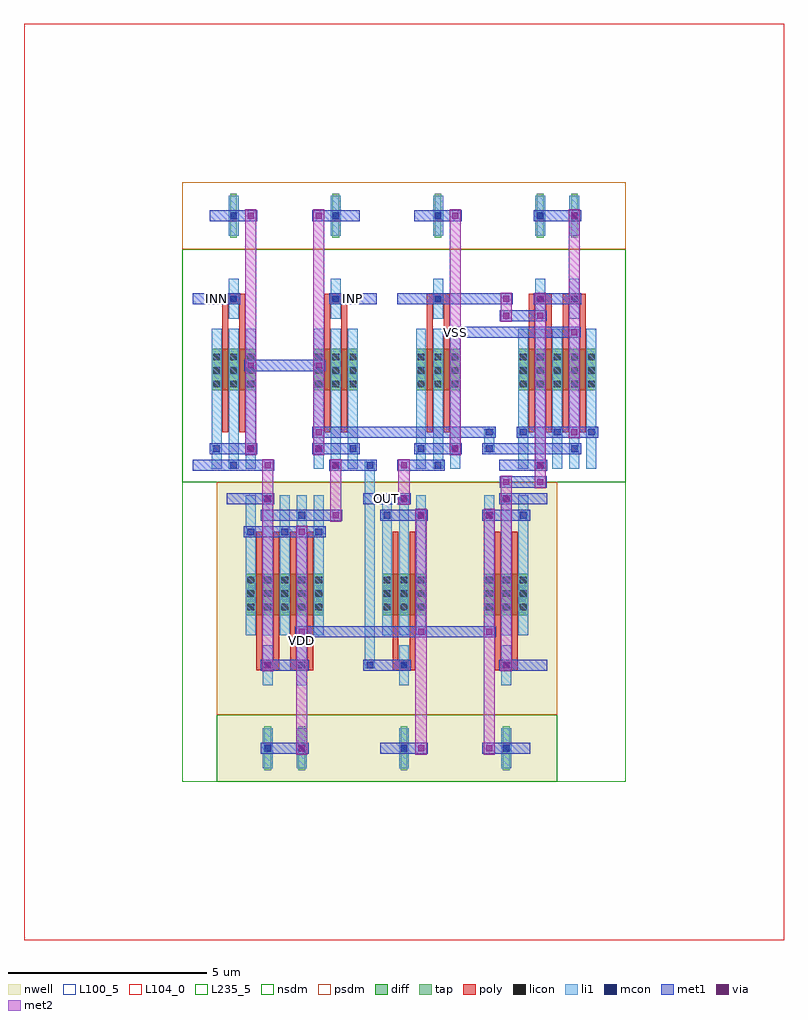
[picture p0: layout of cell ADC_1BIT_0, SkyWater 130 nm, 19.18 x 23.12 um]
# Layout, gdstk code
from math import pi, radians
import gdstk
lib = gdstk.Library(unit=1e-6, precision=1e-09)
def R(c, l, rs):  # rectangles x0, y0, x1, y1
    for r in rs: c.add(gdstk.rectangle(r[:2], r[2:], *l))
def A(c, l, x, y, w, h, nx, ny, dx, dy):  # array of equal rectangles
    R(c, l, [(x+i*dx, y+j*dy, x+i*dx+w, y+j*dy+h) for i in range(nx) for j in range(ny)])
def P(c, l, *ps):  # polygons
    for p in ps: c.add(gdstk.Polygon(p, *l))
nwell = (64, 20)
diff = (65, 20)
tap = (65, 44)
poly = (66, 20)
licon = (66, 44)
li1 = (67, 20)
mcon = (67, 44)
met1 = (68, 20)
via = (68, 44)
met2 = (69, 20)
nsdm = (93, 44)
psdm = (94, 20)
L100_5 = (100, 5)
L104_0 = (104, 0)
L235_5 = (235, 5)

scm_nmos_43308780_x1_y1_ = lib.new_cell('SCM_NMOS_43308780_X1_Y1_1727355101_1727355100')
R(scm_nmos_43308780_x1_y1_, diff, [(0.735,2.31,2.705,3.36)])
R(scm_nmos_43308780_x1_y1_, tap, [(1.205,6.16,1.375,7.28), (2.065,6.16,2.235,7.28)])
A(scm_nmos_43308780_x1_y1_, poly, 1, 1.26, 0.15, 3.36, 4, 1, 0.43, 0)
R(scm_nmos_43308780_x1_y1_, poly, [(1,4.485,1.58,4.755), (1.86,4.485,2.44,4.755)])
A(scm_nmos_43308780_x1_y1_, licon, 0.775, 2.39, 0.17, 0.17, 3, 3, 0.43, 0.34)
A(scm_nmos_43308780_x1_y1_, licon, 1.635, 2.39, 0.17, 0.17, 3, 3, 0.43, 0.34)
R(scm_nmos_43308780_x1_y1_, licon, [(1.205,4.535,1.375,4.705), (2.065,4.535,2.235,4.705), (1.205,6.635,1.375,6.805), (2.065,6.635,2.235,6.805)])
A(scm_nmos_43308780_x1_y1_, li1, 0.735, 0.335, 0.25, 3.53, 5, 1, 0.43, 0)
R(scm_nmos_43308780_x1_y1_, li1, [(1.165,4.115,1.415,5.125), (2.025,4.115,2.275,5.125), (1.165,6.215,1.415,7.225), (2.025,6.215,2.275,7.225)])
A(scm_nmos_43308780_x1_y1_, mcon, 0.775, 1.175, 0.17, 0.17, 3, 1, 0.86, 0)
R(scm_nmos_43308780_x1_y1_, mcon, [(1.205,0.335,1.375,0.505), (2.065,0.755,2.235,0.925), (1.205,4.535,1.375,4.705), (2.065,4.535,2.235,4.705), (1.205,6.635,1.375,6.805), (2.065,6.635,2.235,6.805)])
R(scm_nmos_43308780_x1_y1_, met1, [(0.26,0.28,1.46,0.56), (1.12,0.7,2.32,0.98), (0.69,1.12,2.75,1.4), (1.12,4.48,2.32,4.76), (1.12,6.58,2.32,6.86)])
R(scm_nmos_43308780_x1_y1_, via, [(1.215,0.345,1.365,0.495), (2.075,1.185,2.225,1.335), (1.215,4.545,1.365,4.695), (2.075,6.645,2.225,6.795)])
R(scm_nmos_43308780_x1_y1_, met2, [(1.15,0.26,1.43,4.78), (2.01,1.1,2.29,6.88)])
R(scm_nmos_43308780_x1_y1_, nsdm, [(0,0,3.44,5.88)])
R(scm_nmos_43308780_x1_y1_, psdm, [(0,5.88,3.44,7.56)])
R(scm_nmos_43308780_x1_y1_, L100_5, [(0,0,3.44,7.56)])

nmos_s_54487678_x1_y1_17 = lib.new_cell('NMOS_S_54487678_X1_Y1_1727355100_1727355100')
R(nmos_s_54487678_x1_y1_17, diff, [(0.735,2.31,1.845,3.36)])
R(nmos_s_54487678_x1_y1_17, tap, [(1.205,6.16,1.375,7.28)])
R(nmos_s_54487678_x1_y1_17, poly, [(1,1.26,1.15,4.62), (1.43,1.26,1.58,4.62), (1,4.485,1.58,4.755)])
A(nmos_s_54487678_x1_y1_17, licon, 0.775, 2.39, 0.17, 0.17, 3, 3, 0.43, 0.34)
R(nmos_s_54487678_x1_y1_17, licon, [(1.205,4.535,1.375,4.705), (1.205,6.635,1.375,6.805)])
A(nmos_s_54487678_x1_y1_17, li1, 0.735, 0.335, 0.25, 3.53, 3, 1, 0.43, 0)
R(nmos_s_54487678_x1_y1_17, li1, [(1.165,4.115,1.415,5.125), (1.165,6.215,1.415,7.225)])
R(nmos_s_54487678_x1_y1_17, mcon, [(1.205,0.335,1.375,0.505), (0.775,0.755,0.945,0.925), (1.635,0.755,1.805,0.925), (1.205,4.535,1.375,4.705), (1.205,6.635,1.375,6.805)])
R(nmos_s_54487678_x1_y1_17, met1, [(0.26,0.28,1.46,0.56), (0.69,0.7,1.89,0.98), (0.26,4.48,1.46,4.76), (0.69,6.58,1.89,6.86)])
R(nmos_s_54487678_x1_y1_17, via, [(1.645,0.765,1.795,0.915), (1.645,6.645,1.795,6.795)])
R(nmos_s_54487678_x1_y1_17, met2, [(1.58,0.68,1.86,6.88)])
R(nmos_s_54487678_x1_y1_17, nsdm, [(0,0,2.58,5.88)])
R(nmos_s_54487678_x1_y1_17, psdm, [(0,5.88,2.58,7.56)])
R(nmos_s_54487678_x1_y1_17, L100_5, [(0,0,2.58,7.56)])

cmb_nmos_2_43145097_0_0_ = lib.new_cell('CMB_NMOS_2_43145097_0_0_1727355100')
R(cmb_nmos_2_43145097_0_0_, met1, [(1.56,3.64,1.88,3.92), (1.56,3.64,1.88,3.92), (1.72,3.64,4.73,3.92), (4.57,3.64,4.89,3.92), (4.57,3.64,4.89,3.92), (2.85,4.06,3.17,4.34), (2.85,4.06,3.17,4.34), (3.01,4.06,3.87,4.34), (3.71,4.06,4.03,4.34), (3.71,4.06,4.03,4.34), (1.29,4.48,3.01,4.76), (2.85,4.48,3.17,4.76), (2.85,4.48,3.17,4.76)])
P(cmb_nmos_2_43145097_0_0_, met1, [(0,0),(0,0),(0,0),(0,0)],
  [(0,0),(0,0),(0,0),(0,0)],
  [(0,0),(0,0),(0,0),(0,0)])
R(cmb_nmos_2_43145097_0_0_, via, [(1.645,3.705,1.795,3.855), (1.645,3.705,1.795,3.855), (4.655,3.705,4.805,3.855), (4.655,3.705,4.805,3.855), (2.935,4.125,3.085,4.275), (2.935,4.125,3.085,4.275), (3.795,4.125,3.945,4.275), (3.795,4.125,3.945,4.275), (2.935,4.545,3.085,4.695), (2.935,4.545,3.085,4.695)])
R(cmb_nmos_2_43145097_0_0_, met2, [(1.58,3.62,1.86,3.94), (1.58,3.62,1.86,3.94), (4.59,3.62,4.87,3.94), (4.59,3.62,4.87,3.94), (2.87,4.04,3.15,4.36), (2.87,4.04,3.15,4.36), (3.73,4.04,4.01,4.36), (3.73,4.04,4.01,4.36), (2.87,4.2,3.15,4.62), (2.87,4.46,3.15,4.78), (2.87,4.46,3.15,4.78)])
P(cmb_nmos_2_43145097_0_0_, met2, [(0,0),(0,0),(0,0),(0,0)],
  [(0,0),(0,0),(0,0),(0,0)],
  [(0,0),(0,0),(0,0),(0,0)])
R(cmb_nmos_2_43145097_0_0_, L235_5, [(0,0,6.02,7.56)])
cmb_nmos_2_43145097_0_0_.add(gdstk.Reference(scm_nmos_43308780_x1_y1_, (2.58,0)))
cmb_nmos_2_43145097_0_0_.add(gdstk.Reference(nmos_s_54487678_x1_y1_17, (0,0)))

scm_pmos_7675836_x1_y1_1 = lib.new_cell('SCM_PMOS_7675836_X1_Y1_1727355104')
R(scm_pmos_7675836_x1_y1_1, nwell, [(0,0,3.44,7.56)])
R(scm_pmos_7675836_x1_y1_1, diff, [(0.735,2.31,2.705,3.36)])
R(scm_pmos_7675836_x1_y1_1, tap, [(1.205,6.16,1.375,7.28), (2.065,6.16,2.235,7.28)])
A(scm_pmos_7675836_x1_y1_1, poly, 1, 1.26, 0.15, 3.36, 4, 1, 0.43, 0)
R(scm_pmos_7675836_x1_y1_1, poly, [(1,4.485,1.58,4.755), (1.86,4.485,2.44,4.755)])
A(scm_pmos_7675836_x1_y1_1, licon, 0.775, 2.39, 0.17, 0.17, 3, 3, 0.43, 0.34)
A(scm_pmos_7675836_x1_y1_1, licon, 1.635, 2.39, 0.17, 0.17, 3, 3, 0.43, 0.34)
R(scm_pmos_7675836_x1_y1_1, licon, [(1.205,4.535,1.375,4.705), (2.065,4.535,2.235,4.705), (1.205,6.635,1.375,6.805), (2.065,6.635,2.235,6.805)])
A(scm_pmos_7675836_x1_y1_1, li1, 0.735, 0.335, 0.25, 3.53, 5, 1, 0.43, 0)
R(scm_pmos_7675836_x1_y1_1, li1, [(1.165,4.115,1.415,5.125), (2.025,4.115,2.275,5.125), (1.165,6.215,1.415,7.225), (2.025,6.215,2.275,7.225)])
A(scm_pmos_7675836_x1_y1_1, mcon, 0.775, 1.175, 0.17, 0.17, 3, 1, 0.86, 0)
R(scm_pmos_7675836_x1_y1_1, mcon, [(1.205,0.335,1.375,0.505), (2.065,0.755,2.235,0.925), (1.205,4.535,1.375,4.705), (2.065,4.535,2.235,4.705), (1.205,6.635,1.375,6.805), (2.065,6.635,2.235,6.805)])
R(scm_pmos_7675836_x1_y1_1, met1, [(0.26,0.28,1.46,0.56), (1.12,0.7,2.32,0.98), (0.69,1.12,2.75,1.4), (1.12,4.48,2.32,4.76), (1.12,6.58,2.32,6.86)])
R(scm_pmos_7675836_x1_y1_1, via, [(1.215,0.345,1.365,0.495), (2.075,1.185,2.225,1.335), (1.215,4.545,1.365,4.695), (2.075,6.645,2.225,6.795)])
R(scm_pmos_7675836_x1_y1_1, met2, [(1.15,0.26,1.43,4.78), (2.01,1.1,2.29,6.88)])
R(scm_pmos_7675836_x1_y1_1, nsdm, [(0,5.88,3.44,7.56)])
R(scm_pmos_7675836_x1_y1_1, psdm, [(0,0,3.44,5.88)])
R(scm_pmos_7675836_x1_y1_1, L100_5, [(0,0,3.44,7.56)])

dcl_pmos_s_36446492_x1_y = lib.new_cell('DCL_PMOS_S_36446492_X1_Y1_1727355101')
R(dcl_pmos_s_36446492_x1_y, nwell, [(0,0,2.58,7.56)])
R(dcl_pmos_s_36446492_x1_y, diff, [(0.735,2.31,1.845,3.36)])
R(dcl_pmos_s_36446492_x1_y, tap, [(1.205,6.16,1.375,7.28)])
R(dcl_pmos_s_36446492_x1_y, poly, [(1,1.26,1.15,4.62), (1.43,1.26,1.58,4.62), (1,4.485,1.58,4.755)])
A(dcl_pmos_s_36446492_x1_y, licon, 0.775, 2.39, 0.17, 0.17, 3, 3, 0.43, 0.34)
R(dcl_pmos_s_36446492_x1_y, licon, [(1.205,4.535,1.375,4.705), (1.205,6.635,1.375,6.805)])
A(dcl_pmos_s_36446492_x1_y, li1, 0.735, 0.335, 0.25, 3.53, 3, 1, 0.43, 0)
R(dcl_pmos_s_36446492_x1_y, li1, [(1.165,4.115,1.415,5.125), (1.165,6.215,1.415,7.225)])
R(dcl_pmos_s_36446492_x1_y, mcon, [(1.205,0.335,1.375,0.505), (0.775,0.755,0.945,0.925), (1.635,0.755,1.805,0.925), (1.205,4.535,1.375,4.705), (1.205,6.635,1.375,6.805)])
R(dcl_pmos_s_36446492_x1_y, met1, [(0.26,0.28,1.46,0.56), (0.69,0.7,1.89,0.98), (0.26,4.48,1.46,4.76), (0.69,6.58,1.89,6.86)])
R(dcl_pmos_s_36446492_x1_y, via, [(1.215,0.345,1.365,0.495), (1.645,0.765,1.795,0.915), (1.215,4.545,1.365,4.695), (1.645,6.645,1.795,6.795)])
R(dcl_pmos_s_36446492_x1_y, met2, [(1.15,0.26,1.43,4.78), (1.58,0.68,1.86,6.88)])
R(dcl_pmos_s_36446492_x1_y, nsdm, [(0,5.88,2.58,7.56)])
R(dcl_pmos_s_36446492_x1_y, psdm, [(0,0,2.58,5.88)])
R(dcl_pmos_s_36446492_x1_y, L100_5, [(0,0,2.58,7.56)])

c_nmos_s_54487678_x1_y1_17 = lib.new_cell('NMOS_S_54487678_X1_Y1_1727355102')
R(c_nmos_s_54487678_x1_y1_17, diff, [(0.735,2.31,1.845,3.36)])
R(c_nmos_s_54487678_x1_y1_17, tap, [(1.205,6.16,1.375,7.28)])
R(c_nmos_s_54487678_x1_y1_17, poly, [(1,1.26,1.15,4.62), (1.43,1.26,1.58,4.62), (1,4.485,1.58,4.755)])
A(c_nmos_s_54487678_x1_y1_17, licon, 0.775, 2.39, 0.17, 0.17, 3, 3, 0.43, 0.34)
R(c_nmos_s_54487678_x1_y1_17, licon, [(1.205,4.535,1.375,4.705), (1.205,6.635,1.375,6.805)])
A(c_nmos_s_54487678_x1_y1_17, li1, 0.735, 0.335, 0.25, 3.53, 3, 1, 0.43, 0)
R(c_nmos_s_54487678_x1_y1_17, li1, [(1.165,4.115,1.415,5.125), (1.165,6.215,1.415,7.225)])
R(c_nmos_s_54487678_x1_y1_17, mcon, [(1.205,0.335,1.375,0.505), (0.775,0.755,0.945,0.925), (1.635,0.755,1.805,0.925), (1.205,4.535,1.375,4.705), (1.205,6.635,1.375,6.805)])
R(c_nmos_s_54487678_x1_y1_17, met1, [(0.26,0.28,1.46,0.56), (0.69,0.7,1.89,0.98), (0.26,4.48,1.46,4.76), (0.69,6.58,1.89,6.86)])
R(c_nmos_s_54487678_x1_y1_17, via, [(1.645,0.765,1.795,0.915), (1.645,6.645,1.795,6.795)])
R(c_nmos_s_54487678_x1_y1_17, met2, [(1.58,0.68,1.86,6.88)])
R(c_nmos_s_54487678_x1_y1_17, nsdm, [(0,0,2.58,5.88)])
R(c_nmos_s_54487678_x1_y1_17, psdm, [(0,5.88,2.58,7.56)])
R(c_nmos_s_54487678_x1_y1_17, L100_5, [(0,0,2.58,7.56)])

pmos_s_87189516_x1_y1_17 = lib.new_cell('PMOS_S_87189516_X1_Y1_1727355103')
R(pmos_s_87189516_x1_y1_17, nwell, [(0,0,2.58,7.56)])
R(pmos_s_87189516_x1_y1_17, diff, [(0.735,2.31,1.845,3.36)])
R(pmos_s_87189516_x1_y1_17, tap, [(1.205,6.16,1.375,7.28)])
R(pmos_s_87189516_x1_y1_17, poly, [(1,1.26,1.15,4.62), (1.43,1.26,1.58,4.62), (1,4.485,1.58,4.755)])
A(pmos_s_87189516_x1_y1_17, licon, 0.775, 2.39, 0.17, 0.17, 3, 3, 0.43, 0.34)
R(pmos_s_87189516_x1_y1_17, licon, [(1.205,4.535,1.375,4.705), (1.205,6.635,1.375,6.805)])
A(pmos_s_87189516_x1_y1_17, li1, 0.735, 0.335, 0.25, 3.53, 3, 1, 0.43, 0)
R(pmos_s_87189516_x1_y1_17, li1, [(1.165,4.115,1.415,5.125), (1.165,6.215,1.415,7.225)])
R(pmos_s_87189516_x1_y1_17, mcon, [(1.205,0.335,1.375,0.505), (0.775,0.755,0.945,0.925), (1.635,0.755,1.805,0.925), (1.205,4.535,1.375,4.705), (1.205,6.635,1.375,6.805)])
R(pmos_s_87189516_x1_y1_17, met1, [(0.26,0.28,1.46,0.56), (0.69,0.7,1.89,0.98), (0.26,4.48,1.46,4.76), (0.69,6.58,1.89,6.86)])
R(pmos_s_87189516_x1_y1_17, via, [(1.645,0.765,1.795,0.915), (1.645,6.645,1.795,6.795)])
R(pmos_s_87189516_x1_y1_17, met2, [(1.58,0.68,1.86,6.88)])
R(pmos_s_87189516_x1_y1_17, nsdm, [(0,5.88,2.58,7.56)])
R(pmos_s_87189516_x1_y1_17, psdm, [(0,0,2.58,5.88)])
R(pmos_s_87189516_x1_y1_17, L100_5, [(0,0,2.58,7.56)])

adc_1bit_0 = lib.new_cell('ADC_1BIT_0')
R(adc_1bit_0, li1, [(4.605,2.855,4.855,3.025), (4.605,2.855,4.855,3.025), (4.605,2.855,4.855,3.025), (4.605,2.855,4.855,3.025), (4.605,2.94,4.855,7.98), (4.605,7.895,4.855,8.065), (4.605,7.895,4.855,8.065), (4.605,7.895,4.855,8.065), (4.605,7.895,4.855,8.065), (7.615,8.315,7.865,8.485), (7.615,8.315,7.865,8.485), (7.615,8.4,7.865,8.82), (7.615,8.735,7.865,8.905), (7.615,8.735,7.865,8.905)])
R(adc_1bit_0, mcon, [(4.645,2.855,4.815,3.025), (4.645,2.855,4.815,3.025), (4.645,2.855,4.815,3.025), (4.645,2.855,4.815,3.025), (4.645,7.895,4.815,8.065), (4.645,7.895,4.815,8.065), (4.645,7.895,4.815,8.065), (4.645,7.895,4.815,8.065), (7.655,8.315,7.825,8.485), (7.655,8.315,7.825,8.485), (7.655,8.735,7.825,8.905), (7.655,8.735,7.825,8.905)])
R(adc_1bit_0, met1, [(4.56,2.8,4.9,3.08), (4.56,2.8,4.9,3.08), (4.56,2.8,4.9,3.08), (4.56,2.8,4.9,3.08), (2.85,3.64,3.17,3.92), (2.85,3.64,3.17,3.92), (2.85,3.64,3.17,3.92), (2.85,3.64,3.17,3.92), (3.01,3.64,6.02,3.92), (5.86,3.64,6.18,3.92), (5.86,3.64,6.18,3.92), (5.86,3.64,6.18,3.92), (5.86,3.64,6.18,3.92), (6.02,3.64,7.74,3.92), (7.58,3.64,7.9,3.92), (7.58,3.64,7.9,3.92), (3.01,6.58,3.87,6.86), (3.71,6.58,4.03,6.86), (3.71,6.58,4.03,6.86), (5.43,7,5.75,7.28), (5.43,7,5.75,7.28), (8.01,7.42,8.33,7.7), (8.01,7.42,8.33,7.7), (8.17,7.42,9.03,7.7), (8.87,7.42,9.19,7.7), (8.87,7.42,9.19,7.7), (1.29,7.84,2.15,8.12), (1.99,7.84,2.31,8.12), (1.99,7.84,2.31,8.12), (3.71,7.84,4.03,8.12), (3.71,7.84,4.03,8.12), (4.56,7.84,4.9,8.12), (4.56,7.84,4.9,8.12), (4.56,7.84,4.9,8.12), (4.56,7.84,4.9,8.12), (5.43,7.84,5.75,8.12), (5.43,7.84,5.75,8.12), (7.57,8.26,7.91,8.54), (7.57,8.26,7.91,8.54), (7.74,8.26,9.03,8.54), (3.28,8.68,3.6,8.96), (3.28,8.68,3.6,8.96), (3.44,8.68,7.74,8.96), (7.57,8.68,7.91,8.96), (7.57,8.68,7.91,8.96), (1.56,10.36,1.88,10.64), (1.56,10.36,1.88,10.64), (1.56,10.36,1.88,10.64), (1.56,10.36,1.88,10.64), (1.72,10.36,3.44,10.64), (3.28,10.36,3.6,10.64), (3.28,10.36,3.6,10.64), (3.28,10.36,3.6,10.64), (3.28,10.36,3.6,10.64)])
P(adc_1bit_0, met1, [(0,0),(0,0),(0,0),(0,0)],
  [(0,0),(0,0),(0,0),(0,0)],
  [(0,0),(0,0),(0,0),(0,0)],
  [(0,0),(0,0),(0,0),(0,0)],
  [(0,0),(0,0),(0,0),(0,0)],
  [(0,0),(0,0),(0,0),(0,0)],
  [(0,0),(0,0),(0,0),(0,0)],
  [(0,0),(0,0),(0,0),(0,0)],
  [(0,0),(0,0),(0,0),(0,0)],
  [(0,0),(0,0),(0,0),(0,0)],
  [(0,0),(0,0),(0,0),(0,0)],
  [(0,0),(0,0),(0,0),(0,0)],
  [(0,0),(0,0),(0,0),(0,0)],
  [(0,0),(0,0),(0,0),(0,0)],
  [(0,0),(0,0),(0,0),(0,0)],
  [(0,0),(0,0),(0,0),(0,0)])
R(adc_1bit_0, via, [(2.935,3.705,3.085,3.855), (2.935,3.705,3.085,3.855), (2.935,3.705,3.085,3.855), (2.935,3.705,3.085,3.855), (5.945,3.705,6.095,3.855), (5.945,3.705,6.095,3.855), (5.945,3.705,6.095,3.855), (5.945,3.705,6.095,3.855), (7.665,3.705,7.815,3.855), (7.665,3.705,7.815,3.855), (3.795,6.645,3.945,6.795), (3.795,6.645,3.945,6.795), (5.515,7.065,5.665,7.215), (5.515,7.065,5.665,7.215), (8.095,7.485,8.245,7.635), (8.095,7.485,8.245,7.635), (8.955,7.485,9.105,7.635), (8.955,7.485,9.105,7.635), (2.075,7.905,2.225,8.055), (2.075,7.905,2.225,8.055), (3.795,7.905,3.945,8.055), (3.795,7.905,3.945,8.055), (5.515,7.905,5.665,8.055), (5.515,7.905,5.665,8.055), (3.365,8.745,3.515,8.895), (3.365,8.745,3.515,8.895), (1.645,10.425,1.795,10.575), (1.645,10.425,1.795,10.575), (1.645,10.425,1.795,10.575), (1.645,10.425,1.795,10.575), (3.365,10.425,3.515,10.575), (3.365,10.425,3.515,10.575), (3.365,10.425,3.515,10.575), (3.365,10.425,3.515,10.575)])
R(adc_1bit_0, met2, [(2.87,3.62,3.15,3.94), (2.87,3.62,3.15,3.94), (2.87,3.62,3.15,3.94), (2.87,3.62,3.15,3.94), (5.88,3.62,6.16,3.94), (5.88,3.62,6.16,3.94), (5.88,3.62,6.16,3.94), (5.88,3.62,6.16,3.94), (7.6,3.62,7.88,3.94), (7.6,3.62,7.88,3.94), (3.73,6.56,4.01,6.88), (3.73,6.56,4.01,6.88), (3.73,6.72,4.01,7.98), (5.45,6.98,5.73,7.3), (5.45,6.98,5.73,7.3), (2.01,7.14,2.29,7.98), (5.45,7.14,5.73,7.98), (8.03,7.14,8.31,7.56), (8.03,7.4,8.31,7.72), (8.03,7.4,8.31,7.72), (8.89,7.4,9.17,7.72), (8.89,7.4,9.17,7.72), (8.89,7.56,9.17,7.98), (2.01,7.82,2.29,8.14), (2.01,7.82,2.29,8.14), (3.73,7.82,4.01,8.14), (3.73,7.82,4.01,8.14), (5.45,7.82,5.73,8.14), (5.45,7.82,5.73,8.14), (3.3,8.66,3.58,8.98), (3.3,8.66,3.58,8.98), (1.58,10.34,1.86,10.66), (1.58,10.34,1.86,10.66), (1.58,10.34,1.86,10.66), (1.58,10.34,1.86,10.66), (3.3,10.34,3.58,10.66), (3.3,10.34,3.58,10.66), (3.3,10.34,3.58,10.66), (3.3,10.34,3.58,10.66)])
P(adc_1bit_0, met2, [(0,0),(0,0),(0,0),(0,0)],
  [(0,0),(0,0),(0,0),(0,0)],
  [(0,0),(0,0),(0,0),(0,0)],
  [(0,0),(0,0),(0,0),(0,0)],
  [(0,0),(0,0),(0,0),(0,0)],
  [(0,0),(0,0),(0,0),(0,0)],
  [(0,0),(0,0),(0,0),(0,0)],
  [(0,0),(0,0),(0,0),(0,0)],
  [(0,0),(0,0),(0,0),(0,0)],
  [(0,0),(0,0),(0,0),(0,0)],
  [(0,0),(0,0),(0,0),(0,0)],
  [(0,0),(0,0),(0,0),(0,0)],
  [(0,0),(0,0),(0,0),(0,0)],
  [(0,0),(0,0),(0,0),(0,0)],
  [(0,0),(0,0),(0,0),(0,0)],
  [(0,0),(0,0),(0,0),(0,0)])
R(adc_1bit_0, L104_0, [(-4,-4,15.18,19.12)])
R(adc_1bit_0, L235_5, [(0,0,11.18,15.12)])
adc_1bit_0.add(gdstk.Reference(cmb_nmos_2_43145097_0_0_, (5.16,7.56)))
adc_1bit_0.add(gdstk.Reference(scm_pmos_7675836_x1_y1_1, (0.86,7.56), x_reflection=True))
adc_1bit_0.add(gdstk.Reference(dcl_pmos_s_36446492_x1_y, (9.46,7.56), rotation=pi))
adc_1bit_0.add(gdstk.Reference(c_nmos_s_54487678_x1_y1_17, (0,7.56)))
adc_1bit_0.add(gdstk.Reference(c_nmos_s_54487678_x1_y1_17, (5.16,7.56), rotation=pi, x_reflection=True))
adc_1bit_0.add(gdstk.Reference(pmos_s_87189516_x1_y1_17, (4.3,7.56), x_reflection=True))
adc_1bit_0.add(gdstk.Label('OUT', (5.16,7.14), layer=68, texttype=5))
adc_1bit_0.add(gdstk.Label('VSS', (6.88,11.34), layer=69, texttype=5))
adc_1bit_0.add(gdstk.Label('VDD', (3.01,3.57), layer=69, texttype=5))
adc_1bit_0.add(gdstk.Label('INN', (0.86,12.18), layer=68, texttype=5))
adc_1bit_0.add(gdstk.Label('INP', (4.3,12.18), layer=68, texttype=5))

lib.write_gds('ADC_1BIT_0.gds')
